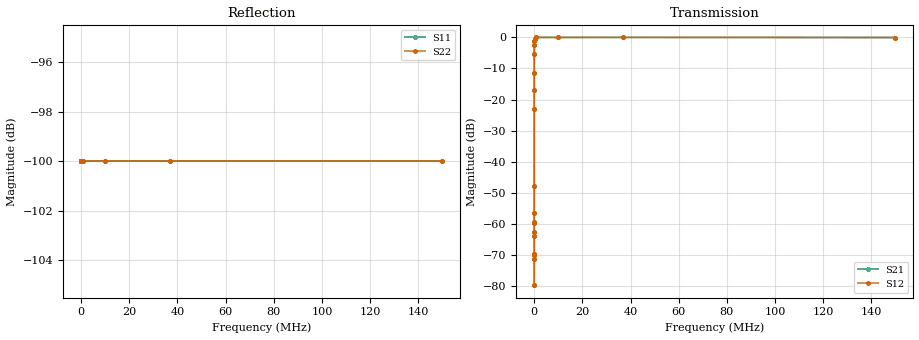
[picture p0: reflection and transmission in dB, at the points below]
! 7/27/2020 1:17 PM
! H:\MS4647B\Production_Data\9437-11\Juan_6\Juan_6_LF_2020-07-27_11-52-44_s2p.s2p
! CORRECTED DATA
# Hz S DB R 50.0
! FREQ  S11DB  S11A  S21DB  S21A  S12DB  S12A  S22DB  S22A
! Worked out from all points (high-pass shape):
!   401 points, 10 Hz to 150 MHz, reference 50 ohm
!   highest |S21| = -0.04 dB at 36.82 MHz (marker M1); lowest = -79.6 dB at 10 Hz (marker M2)
!   |S21| within 3 dB of the highest: 35.12 kHz to end of sweep
!   lowest |S11| = -100.0 dB at 10 Hz (marker M3), VSWR 1.00, Z = 50 + j0 ohm
!   |S11| at or under -10 dB: start of sweep to end of sweep
!   |S22| runs from -100.0 to -100.0 dB; largest |S21 - S12| = 0
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10  -100.00 0.0  -79.58 -79.6  -79.58 -79.6  -100.00 0.0
11.31933  -100.00 0.0  -71.12 -71.1  -71.12 -71.1  -100.00 0.0
11.79671  -100.00 0.0  -70.04 -70.0  -70.04 -70.0  -100.00 0.0
12.29423  -100.00 0.0  -69.45 -69.5  -69.45 -69.5  -100.00 0.0
17.10893  -100.00 0.0  -69.69 -69.7  -69.69 -69.7  -100.00 0.0
26.95042  -100.00 0.0  -63.79 -63.8  -63.79 -63.8  -100.00 0.0
34.53082  -100.00 0.0  -62.58 -62.6  -62.58 -62.6  -100.00 0.0
42.45296  -100.00 0.0  -59.69 -59.7  -59.69 -59.7  -100.00 0.0
48.0539  -100.00 0.0  -59.35 -59.3  -59.35 -59.3  -100.00 0.0
59.07855  -100.00 0.0  -56.38 -56.4  -56.38 -56.4  -100.00 0.0
159.2191  -100.00 0.0  -47.84 -47.8  -47.84 -47.8  -100.00 0.0
2535.074  -100.00 0.0  -22.91 -22.9  -22.91 -22.9  -100.00 0.0
5116.517  -100.00 0.0  -16.93 -16.9  -16.93 -16.9  -100.00 0.0
9908.732  -100.00 0.0  -11.39 -11.4  -11.39 -11.4  -100.00 0.0
22637.2  -100.00 0.0  -5.34 -5.3  -5.34 -5.3  -100.00 0.0
40363.22  -100.00 0.0  -2.50 -2.5  -2.50 -2.5  -100.00 0.0
63581.15  -100.00 0.0  -1.18 -1.2  -1.18 -1.2  -100.00 0.0
108780.6  -100.00 0.0  -0.47 -0.5  -0.47 -0.5  -100.00 0.0
616653.1  -100.00 0.0  -0.05 -0.1  -0.05 -0.1  -100.00 0.0
9818298  -100.00 0.0  -0.05 -0.0  -0.05 -0.0  -100.00 0.0
3.682337e7  -100.00 0.0  -0.04 -0.0  -0.04 -0.0  -100.00 0.0
1.5e8  -100.00 0.0  -0.08 -0.1  -0.08 -0.1  -100.00 0.0
